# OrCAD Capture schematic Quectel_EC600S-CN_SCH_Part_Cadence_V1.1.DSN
size A0

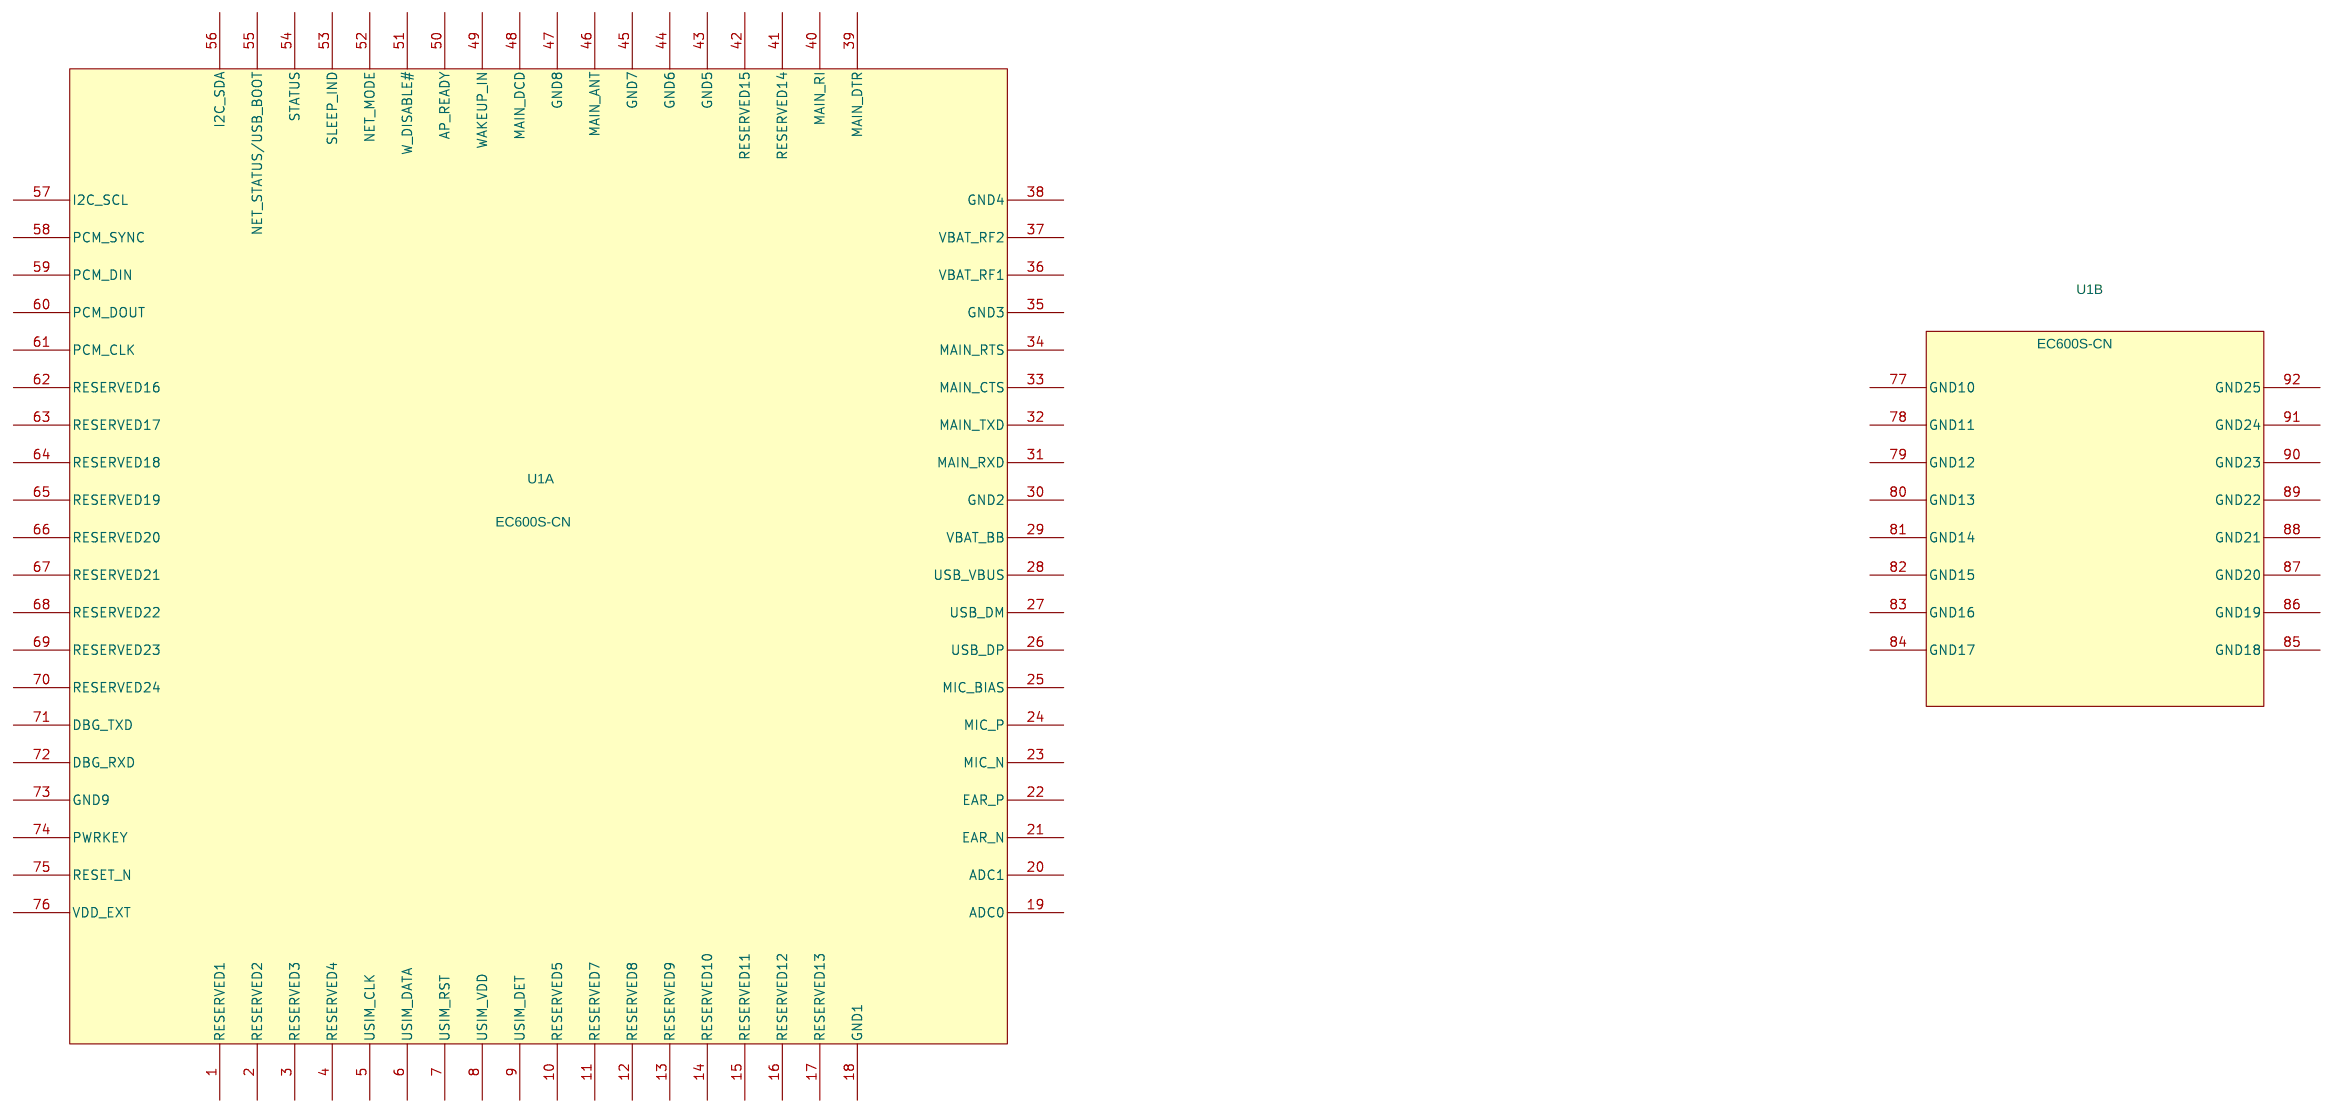
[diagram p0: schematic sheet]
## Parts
U1  EC600S-CN  [EC600S-CN]  (sections A,B)

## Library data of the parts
U1 = EC600S-CN

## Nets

Not connected (* = marked no-connect by the designer): U1 1(RESERVED1) 2(RESERVED2) 3(RESERVED3) 4(RESERVED4) 5(USIM_CLK) 6(USIM_DATA) 7(USIM_RST) 8(USIM_VDD) 9(USIM_DET) 10(RESERVED5) 11(RESERVED7) 12(RESERVED8) 13(RESERVED9) 14(RESERVED10) 15(RESERVED11) 16(RESERVED12) 17(RESERVED13) 18(GND1) 19(ADC0) 20(ADC1) 21(EAR_N) 22(EAR_P) 23(MIC_N) 24(MIC_P) 25(MIC_BIAS) 26(USB_DP) 27(USB_DM) 28(USB_VBUS) 29(VBAT_BB) 30(GND2) 31(MAIN_RXD) 32(MAIN_TXD) 33(MAIN_CTS) 34(MAIN_RTS) 35(GND3) 36(VBAT_RF1) 37(VBAT_RF2) 38(GND4) 39(MAIN_DTR) 40(MAIN_RI) 41(RESERVED14) 42(RESERVED15) 43(GND5) 44(GND6) 45(GND7) 46(MAIN_ANT) 47(GND8) 48(MAIN_DCD) 49(WAKEUP_IN) 50(AP_READY) 51(W_DISABLE#) 52(NET_MODE) 53(SLEEP_IND) 54(STATUS) 55(NET_STATUS/USB_BOOT) 56(I2C_SDA) 57(I2C_SCL) 58(PCM_SYNC) 59(PCM_DIN) 60(PCM_DOUT) 61(PCM_CLK) 62(RESERVED16) 63(RESERVED17) 64(RESERVED18) 65(RESERVED19) 66(RESERVED20) 67(RESERVED21) 68(RESERVED22) 69(RESERVED23) 70(RESERVED24) 71(DBG_TXD) 72(DBG_RXD) 73(GND9) 74(PWRKEY) 75(RESET_N) 76(VDD_EXT) 77(GND10) 78(GND11) 79(GND12) 80(GND13) 81(GND14) 82(GND15) 83(GND16) 84(GND17) 85(GND18) 86(GND19) 87(GND20) 88(GND21) 89(GND22) 90(GND23) 91(GND24) 92(GND25)
